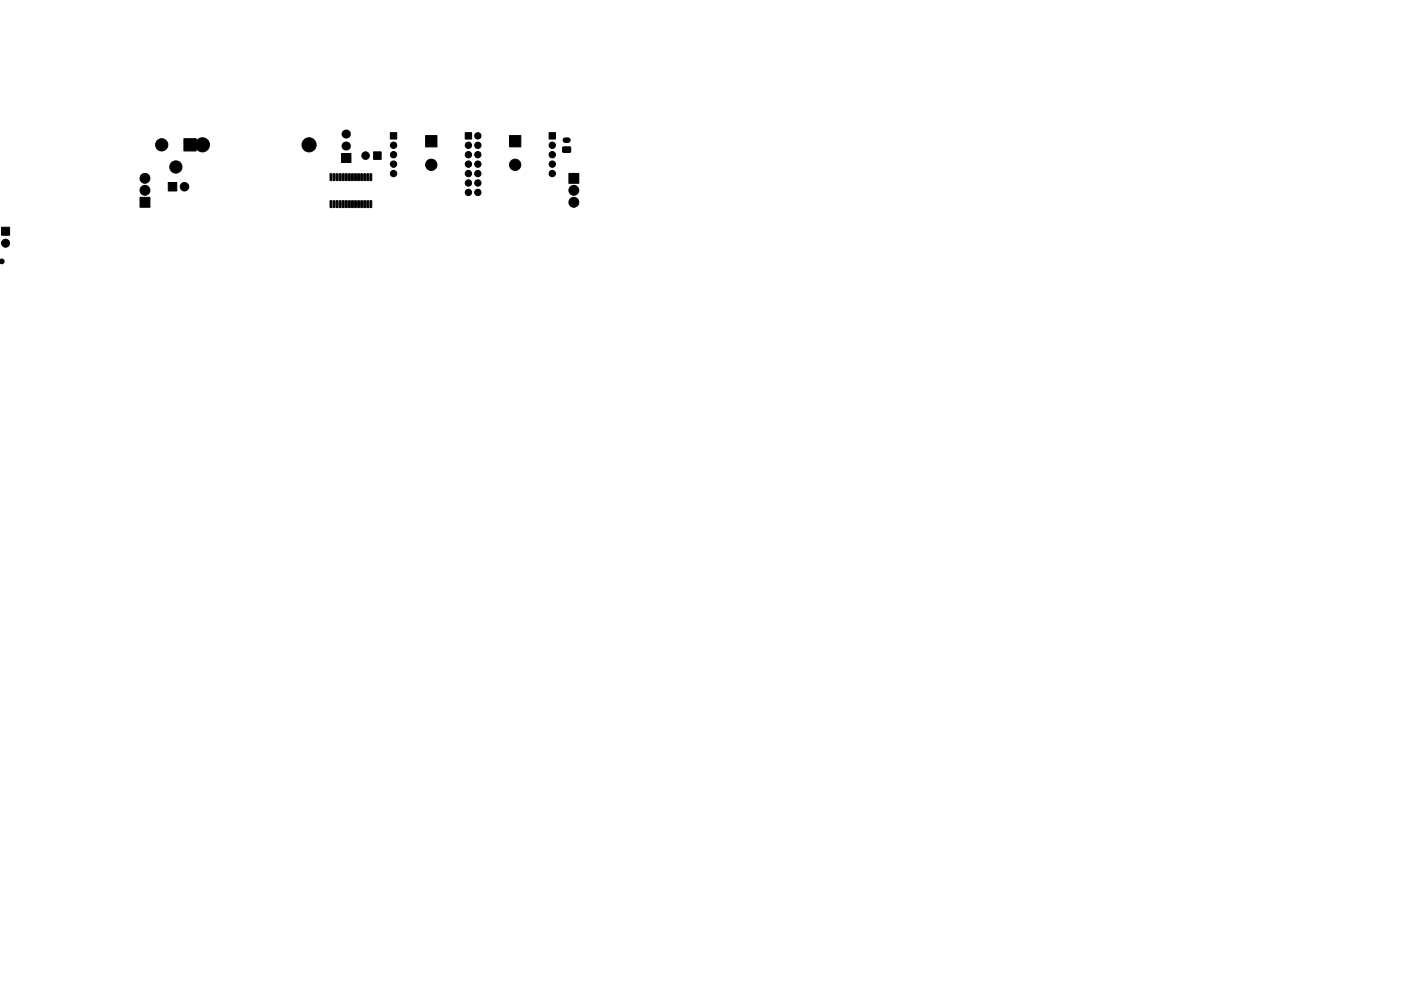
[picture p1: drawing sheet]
<svg xmlns="http://www.w3.org/2000/svg" width="297mm" height="210mm" viewBox="0 0 297 210" stroke-linecap="round" stroke-linejoin="round" font-family="sans-serif">
<g fill="#000" stroke="#000" stroke-width=".21">
<path d="M39 29.4h2.6v2.6h-2.6zM70 36.9h.4l-.1 1.4-.3-.1zM70.7 36.9h.3l-.1 1.4-.3-.1zM71.3 36.9h.4l-.1 1.4-.3-.1zM72 36.9h.3l-.1 1.4-.3-.1zM72.6 36.9h.4l-.1 1.4-.3-.1zM73.3 36.9h.3l-.1 1.4-.3-.1zM73.9 36.9h.4l-.1 1.4-.3-.1zM72.4 32.6h2v1.9h-2zM74.6 36.9h.3l-.1 1.4-.3-.1zM75.2 36.9h.4l-.1 1.4-.3-.1zM75.9 36.9h.3l-.1 1.4-.3-.1z"/>
<path d="M76.5 36.9h.4l-.1 1.4-.3-.1zM77.2 36.9h.3l-.1 1.4-.3-.1zM77.8 36.9h.4l-.1 1.4-.3-.1zM78.5 36.9h.3l-.1 1.4-.3-.1zM79.2 32.2h1.6v1.6h-1.6zM82.8 28.1h1.3v1.4h-1.3zM90.2 28.8h2.4v2.4h-2.4zM98.6 28.1h1.4v1.4h-1.4zM108 28.8h2.4v2.4h-2.4zM116.4 28.1h1.4v1.4h-1.4zM120.6 36.8h2.1v2.1h-2.1zM119.3 31.2h1.6l.1 1-1.6 .1z"/>
<path d="M.3 48.2h1.7v1.7h-1.7zM29.7 41.9h2.1v2.1h-2.1zM35.7 38.7h1.8v1.8h-1.8zM70 42.6l.4 .1-.1 1.3h-.3zM70.7 42.6l.3 .1-.1 1.3h-.3zM71.3 42.6l.4 .1-.1 1.3h-.3zM72 42.6l.3 .1-.1 1.3h-.3zM72.6 42.6l.4 .1-.1 1.3h-.3zM73.3 42.6l.3 .1-.1 1.3h-.3zM73.9 42.6l.4 .1-.1 1.3h-.3zM74.6 42.6l.3 .1-.1 1.3h-.3zM75.2 42.6l.4 .1-.1 1.3h-.3z"/>
<path d="M75.9 42.6l.3 .1-.1 1.3h-.3zM76.5 42.6l.4 .1-.1 1.3h-.3zM77.2 42.6l.3 .1-.1 1.3h-.3zM77.8 42.6l.4 .1-.1 1.3h-.3zM78.5 42.6l.3 .1-.1 1.3h-.3z"/>
<circle cx="30.7" cy="37.8" r="1.05"/>
<circle cx="34.3" cy="30.7" r="1.3"/>
<circle cx="37.3" cy="35.4" r="1.3"/>
<circle cx="39.1" cy="39.6" r=".9"/>
<circle cx="42.9" cy="30.7" r="1.5"/>
<circle cx="65.5" cy="30.7" r="1.5"/>
<circle cx="77.5" cy="33" r=".8"/>
<circle cx="83.4" cy="30.8" r=".67"/>
<circle cx="83.4" cy="32.8" r=".67"/>
<circle cx="83.4" cy="34.8" r=".67"/>
<circle cx="83.4" cy="36.8" r=".67"/>
<circle cx="91.4" cy="35" r="1.2"/>
<circle cx="99.3" cy="30.8" r=".67"/>
<circle cx="99.3" cy="32.8" r=".67"/>
<circle cx="99.3" cy="34.8" r=".67"/>
<circle cx="99.3" cy="38.8" r=".67"/>
<circle cx="99.3" cy="36.8" r=".67"/>
<circle cx="101.3" cy="30.8" r=".67"/>
<circle cx="101.3" cy="28.8" r=".67"/>
<circle cx="101.3" cy="32.8" r=".67"/>
<circle cx="101.3" cy="34.8" r=".67"/>
<circle cx="101.3" cy="38.8" r=".67"/>
<circle cx="101.3" cy="36.8" r=".67"/>
<circle cx="109.2" cy="35" r="1.2"/>
<circle cx="117.1" cy="30.8" r=".67"/>
<circle cx="117.1" cy="32.8" r=".67"/>
<circle cx="117.1" cy="34.8" r=".67"/>
<circle cx="117.1" cy="36.8" r=".67"/>
<circle cx=".4" cy="55.5" r=".48"/>
<circle cx="1.2" cy="51.6" r=".85"/>
<circle cx="30.7" cy="40.4" r="1.05"/>
<circle cx="99.3" cy="40.8" r=".67"/>
<circle cx="101.3" cy="40.8" r=".67"/>
<circle cx="121.7" cy="42.9" r="1.05"/>
<circle cx="121.7" cy="40.4" r="1.05"/>
</g>
<path d="M73.4 28.4h.1M73.4 31h.1" fill="none" stroke="#000" stroke-width="1.9"/>
<path d="M119.9 29.7h.5" fill="none" stroke="#000" stroke-width="1.2"/>
</svg>
